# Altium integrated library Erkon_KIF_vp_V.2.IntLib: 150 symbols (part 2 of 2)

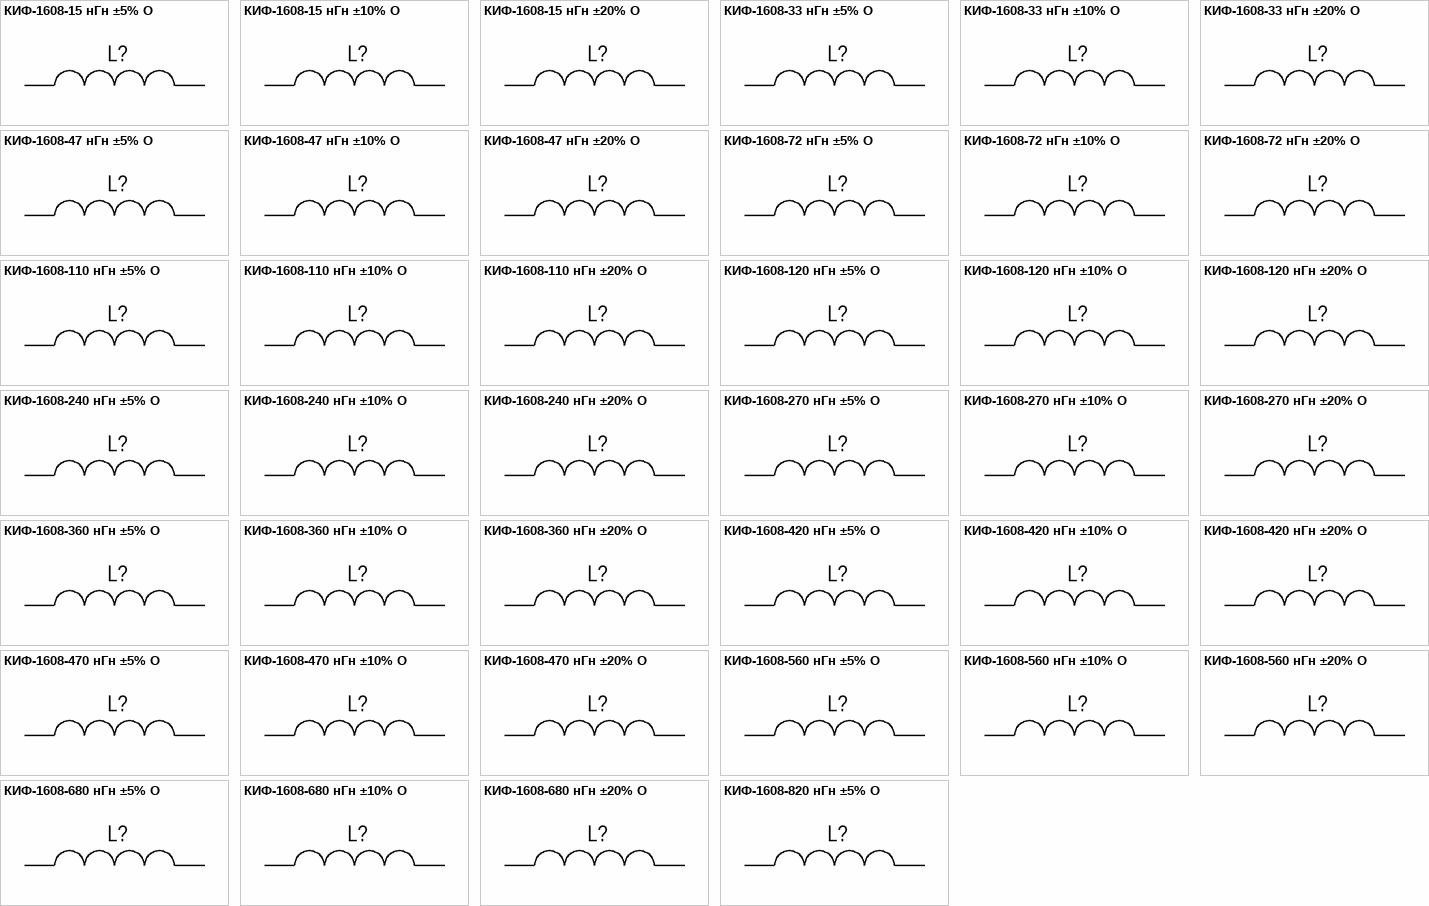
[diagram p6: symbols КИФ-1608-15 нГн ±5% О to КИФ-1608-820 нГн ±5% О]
## КИФ-1608-360 нГн ±10% О
designator L?, comment 360 нГн ±10%  (value not drawn)
Катушка индуктивности с ферритовым сердечником; Номиналиная индуктивность: 360 нГн; Добротность, не менее: 10; Резонансная частота, не менее: 0.7 ГГц; Сопротивление обмотки постоянноми току, не более: 0.33 Ом; Допустимый ток обмотки: 650 мА; Диапазон рабочих температур: от -60 до +125 ℃; Упаковка: Катушка и лента; Типоразмер: 1608 (0603); Технология монтажа: SMT; Изготовитель: АО "НПО "ЭРКОН"
footprint КИФ-1608-О (Катушка индуктивности с ферритовым сердечником типоразмер 1608(0805))
pins: 1, 2

## КИФ-1608-360 нГн ±20% О
designator L?, comment 360 нГн ±20%  (value not drawn)
Катушка индуктивности с ферритовым сердечником; Номиналиная индуктивность: 360 нГн; Добротность, не менее: 10; Резонансная частота, не менее: 0.7 ГГц; Сопротивление обмотки постоянноми току, не более: 0.33 Ом; Допустимый ток обмотки: 650 мА; Диапазон рабочих температур: от -60 до +125 ℃; Упаковка: Катушка и лента; Типоразмер: 1608 (0603); Технология монтажа: SMT; Изготовитель: АО "НПО "ЭРКОН"
footprint КИФ-1608-О (Катушка индуктивности с ферритовым сердечником типоразмер 1608(0805))
pins: 1, 2

## КИФ-1608-420 нГн ±5% О
designator L?, comment 420 нГн ±5%  (value not drawn)
Катушка индуктивности с ферритовым сердечником; Номиналиная индуктивность: 420 нГн; Добротность, не менее: 10; Резонансная частота, не менее: 0.685 ГГц; Сопротивление обмотки постоянноми току, не более: 0.5 Ом; Допустимый ток обмотки: 610 мА; Диапазон рабочих температур: от -60 до +125 ℃; Упаковка: Катушка и лента; Типоразмер: 1608 (0603); Технология монтажа: SMT; Изготовитель: АО "НПО "ЭРКОН"
footprint КИФ-1608-О (Катушка индуктивности с ферритовым сердечником типоразмер 1608(0805))
pins: 1, 2

## КИФ-1608-420 нГн ±10% О
designator L?, comment 420 нГн ±10%  (value not drawn)
Катушка индуктивности с ферритовым сердечником; Номиналиная индуктивность: 420 нГн; Добротность, не менее: 10; Резонансная частота, не менее: 0.685 ГГц; Сопротивление обмотки постоянноми току, не более: 0.5 Ом; Допустимый ток обмотки: 610 мА; Диапазон рабочих температур: от -60 до +125 ℃; Упаковка: Катушка и лента; Типоразмер: 1608 (0603); Технология монтажа: SMT; Изготовитель: АО "НПО "ЭРКОН"
footprint КИФ-1608-О (Катушка индуктивности с ферритовым сердечником типоразмер 1608(0805))
pins: 1, 2

## КИФ-1608-420 нГн ±20% О
designator L?, comment 420 нГн ±20%  (value not drawn)
Катушка индуктивности с ферритовым сердечником; Номиналиная индуктивность: 420 нГн; Добротность, не менее: 10; Резонансная частота, не менее: 0.685 ГГц; Сопротивление обмотки постоянноми току, не более: 0.5 Ом; Допустимый ток обмотки: 610 мА; Диапазон рабочих температур: от -60 до +125 ℃; Упаковка: Катушка и лента; Типоразмер: 1608 (0603); Технология монтажа: SMT; Изготовитель: АО "НПО "ЭРКОН"
footprint КИФ-1608-О (Катушка индуктивности с ферритовым сердечником типоразмер 1608(0805))
pins: 1, 2

## КИФ-1608-470 нГн ±5% О
designator L?, comment 470 нГн ±5%  (value not drawn)
Катушка индуктивности с ферритовым сердечником; Номиналиная индуктивность: 470 нГн; Добротность, не менее: 10; Резонансная частота, не менее: 0.575 ГГц; Сопротивление обмотки постоянноми току, не более: 0.58 Ом; Допустимый ток обмотки: 610 мА; Диапазон рабочих температур: от -60 до +125 ℃; Упаковка: Катушка и лента; Типоразмер: 1608 (0603); Технология монтажа: SMT; Изготовитель: АО "НПО "ЭРКОН"
footprint КИФ-1608-О (Катушка индуктивности с ферритовым сердечником типоразмер 1608(0805))
pins: 1, 2

## КИФ-1608-470 нГн ±10% О
designator L?, comment 470 нГн ±10%  (value not drawn)
Катушка индуктивности с ферритовым сердечником; Номиналиная индуктивность: 470 нГн; Добротность, не менее: 10; Резонансная частота, не менее: 0.575 ГГц; Сопротивление обмотки постоянноми току, не более: 0.58 Ом; Допустимый ток обмотки: 610 мА; Диапазон рабочих температур: от -60 до +125 ℃; Упаковка: Катушка и лента; Типоразмер: 1608 (0603); Технология монтажа: SMT; Изготовитель: АО "НПО "ЭРКОН"
footprint КИФ-1608-О (Катушка индуктивности с ферритовым сердечником типоразмер 1608(0805))
pins: 1, 2

## КИФ-1608-470 нГн ±20% О
designator L?, comment 470 нГн ±20%  (value not drawn)
Катушка индуктивности с ферритовым сердечником; Номиналиная индуктивность: 470 нГн; Добротность, не менее: 10; Резонансная частота, не менее: 0.575 ГГц; Сопротивление обмотки постоянноми току, не более: 0.58 Ом; Допустимый ток обмотки: 610 мА; Диапазон рабочих температур: от -60 до +125 ℃; Упаковка: Катушка и лента; Типоразмер: 1608 (0603); Технология монтажа: SMT; Изготовитель: АО "НПО "ЭРКОН"
footprint КИФ-1608-О (Катушка индуктивности с ферритовым сердечником типоразмер 1608(0805))
pins: 1, 2

## КИФ-1608-560 нГн ±5% О
designator L?, comment 560 нГн ±5%  (value not drawn)
Катушка индуктивности с ферритовым сердечником; Номиналиная индуктивность: 560 нГн; Добротность, не менее: 10; Резонансная частота, не менее: 0.515 ГГц; Сопротивление обмотки постоянноми току, не более: 0.6 Ом; Допустимый ток обмотки: 530 мА; Диапазон рабочих температур: от -60 до +125 ℃; Упаковка: Катушка и лента; Типоразмер: 1608 (0603); Технология монтажа: SMT; Изготовитель: АО "НПО "ЭРКОН"
footprint КИФ-1608-О (Катушка индуктивности с ферритовым сердечником типоразмер 1608(0805))
pins: 1, 2

## КИФ-1608-560 нГн ±10% О
designator L?, comment 560 нГн ±10%  (value not drawn)
Катушка индуктивности с ферритовым сердечником; Номиналиная индуктивность: 560 нГн; Добротность, не менее: 10; Резонансная частота, не менее: 0.515 ГГц; Сопротивление обмотки постоянноми току, не более: 0.6 Ом; Допустимый ток обмотки: 530 мА; Диапазон рабочих температур: от -60 до +125 ℃; Упаковка: Катушка и лента; Типоразмер: 1608 (0603); Технология монтажа: SMT; Изготовитель: АО "НПО "ЭРКОН"
footprint КИФ-1608-О (Катушка индуктивности с ферритовым сердечником типоразмер 1608(0805))
pins: 1, 2

## КИФ-1608-560 нГн ±20% О
designator L?, comment 560 нГн ±20%  (value not drawn)
Катушка индуктивности с ферритовым сердечником; Номиналиная индуктивность: 560 нГн; Добротность, не менее: 10; Резонансная частота, не менее: 0.515 ГГц; Сопротивление обмотки постоянноми току, не более: 0.6 Ом; Допустимый ток обмотки: 530 мА; Диапазон рабочих температур: от -60 до +125 ℃; Упаковка: Катушка и лента; Типоразмер: 1608 (0603); Технология монтажа: SMT; Изготовитель: АО "НПО "ЭРКОН"
footprint КИФ-1608-О (Катушка индуктивности с ферритовым сердечником типоразмер 1608(0805))
pins: 1, 2

## КИФ-1608-680 нГн ±5% О
designator L?, comment 680 нГн ±5%  (value not drawn)
Катушка индуктивности с ферритовым сердечником; Номиналиная индуктивность: 680 нГн; Добротность, не менее: 10; Резонансная частота, не менее: 0.53 ГГц; Сопротивление обмотки постоянноми току, не более: 0.65 Ом; Допустимый ток обмотки: 490 мА; Диапазон рабочих температур: от -60 до +125 ℃; Упаковка: Катушка и лента; Типоразмер: 1608 (0603); Технология монтажа: SMT; Изготовитель: АО "НПО "ЭРКОН"
footprint КИФ-1608-О (Катушка индуктивности с ферритовым сердечником типоразмер 1608(0805))
pins: 1, 2

## КИФ-1608-680 нГн ±10% О
designator L?, comment 680 нГн ±10%  (value not drawn)
Катушка индуктивности с ферритовым сердечником; Номиналиная индуктивность: 680 нГн; Добротность, не менее: 10; Резонансная частота, не менее: 0.53 ГГц; Сопротивление обмотки постоянноми току, не более: 0.65 Ом; Допустимый ток обмотки: 490 мА; Диапазон рабочих температур: от -60 до +125 ℃; Упаковка: Катушка и лента; Типоразмер: 1608 (0603); Технология монтажа: SMT; Изготовитель: АО "НПО "ЭРКОН"
footprint КИФ-1608-О (Катушка индуктивности с ферритовым сердечником типоразмер 1608(0805))
pins: 1, 2

## КИФ-1608-680 нГн ±20% О
designator L?, comment 680 нГн ±20%  (value not drawn)
Катушка индуктивности с ферритовым сердечником; Номиналиная индуктивность: 680 нГн; Добротность, не менее: 10; Резонансная частота, не менее: 0.53 ГГц; Сопротивление обмотки постоянноми току, не более: 0.65 Ом; Допустимый ток обмотки: 490 мА; Диапазон рабочих температур: от -60 до +125 ℃; Упаковка: Катушка и лента; Типоразмер: 1608 (0603); Технология монтажа: SMT; Изготовитель: АО "НПО "ЭРКОН"
footprint КИФ-1608-О (Катушка индуктивности с ферритовым сердечником типоразмер 1608(0805))
pins: 1, 2

## КИФ-1608-820 нГн ±5% О
designator L?, comment 820 нГн ±5%  (value not drawn)
Катушка индуктивности с ферритовым сердечником; Номиналиная индуктивность: 820 нГн; Добротность, не менее: 10; Резонансная частота, не менее: 0.325 ГГц; Сопротивление обмотки постоянноми току, не более: 0.75 Ом; Допустимый ток обмотки: 420 мА; Диапазон рабочих температур: от -60 до +125 ℃; Упаковка: Катушка и лента; Типоразмер: 1608 (0603); Технология монтажа: SMT; Изготовитель: АО "НПО "ЭРКОН"
footprint КИФ-1608-О (Катушка индуктивности с ферритовым сердечником типоразмер 1608(0805))
pins: 1, 2


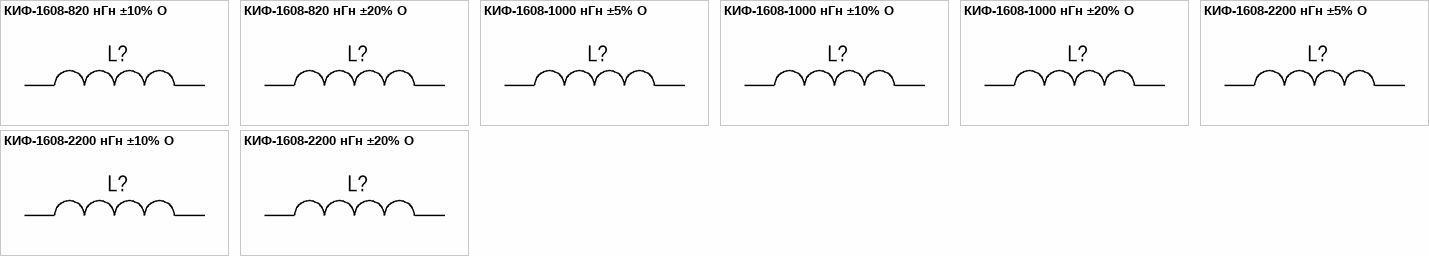
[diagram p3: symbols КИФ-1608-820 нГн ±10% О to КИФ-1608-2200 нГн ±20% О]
## КИФ-1608-820 нГн ±10% О
designator L?, comment 820 нГн ±10%  (value not drawn)
Катушка индуктивности с ферритовым сердечником; Номиналиная индуктивность: 820 нГн; Добротность, не менее: 10; Резонансная частота, не менее: 0.325 ГГц; Сопротивление обмотки постоянноми току, не более: 0.75 Ом; Допустимый ток обмотки: 420 мА; Диапазон рабочих температур: от -60 до +125 ℃; Упаковка: Катушка и лента; Типоразмер: 1608 (0603); Технология монтажа: SMT; Изготовитель: АО "НПО "ЭРКОН"
footprint КИФ-1608-О (Катушка индуктивности с ферритовым сердечником типоразмер 1608(0805))
pins: 1, 2

## КИФ-1608-820 нГн ±20% О
designator L?, comment 820 нГн ±20%  (value not drawn)
Катушка индуктивности с ферритовым сердечником; Номиналиная индуктивность: 820 нГн; Добротность, не менее: 10; Резонансная частота, не менее: 0.325 ГГц; Сопротивление обмотки постоянноми току, не более: 0.75 Ом; Допустимый ток обмотки: 420 мА; Диапазон рабочих температур: от -60 до +125 ℃; Упаковка: Катушка и лента; Типоразмер: 1608 (0603); Технология монтажа: SMT; Изготовитель: АО "НПО "ЭРКОН"
footprint КИФ-1608-О (Катушка индуктивности с ферритовым сердечником типоразмер 1608(0805))
pins: 1, 2

## КИФ-1608-1000 нГн ±5% О
designator L?, comment 1000 нГн ±5%  (value not drawn)
Катушка индуктивности с ферритовым сердечником; Добротность, не менее: 10; Резонансная частота, не менее: 0.4 ГГц; Сопротивление обмотки постоянноми току, не более: 0.8 Ом; Допустимый ток обмотки: 400 мА; Диапазон рабочих температур: от -60 до +125 ℃; Упаковка: Катушка и лента; Типоразмер: 1608 (0603); Технология монтажа: SMT; Изготовитель: АО "НПО "ЭРКОН"
footprint КИФ-1608-О (Катушка индуктивности с ферритовым сердечником типоразмер 1608(0805))
pins: 1, 2

## КИФ-1608-1000 нГн ±10% О
designator L?, comment 1000 нГн ±10%  (value not drawn)
Катушка индуктивности с ферритовым сердечником; Добротность, не менее: 10; Резонансная частота, не менее: 0.4 ГГц; Сопротивление обмотки постоянноми току, не более: 0.8 Ом; Допустимый ток обмотки: 400 мА; Диапазон рабочих температур: от -60 до +125 ℃; Упаковка: Катушка и лента; Типоразмер: 1608 (0603); Технология монтажа: SMT; Изготовитель: АО "НПО "ЭРКОН"
footprint КИФ-1608-О (Катушка индуктивности с ферритовым сердечником типоразмер 1608(0805))
pins: 1, 2

## КИФ-1608-1000 нГн ±20% О
designator L?, comment 1000 нГн ±20%  (value not drawn)
Катушка индуктивности с ферритовым сердечником; Добротность, не менее: 10; Резонансная частота, не менее: 0.4 ГГц; Сопротивление обмотки постоянноми току, не более: 0.8 Ом; Допустимый ток обмотки: 400 мА; Диапазон рабочих температур: от -60 до +125 ℃; Упаковка: Катушка и лента; Типоразмер: 1608 (0603); Технология монтажа: SMT; Изготовитель: АО "НПО "ЭРКОН"
footprint КИФ-1608-О (Катушка индуктивности с ферритовым сердечником типоразмер 1608(0805))
pins: 1, 2

## КИФ-1608-2200 нГн ±5% О
designator L?, comment 2200 нГн ±5%  (value not drawn)
Катушка индуктивности с ферритовым сердечником; Добротность, не менее: 10; Резонансная частота, не менее: 0.085 ГГц; Сопротивление обмотки постоянноми току, не более: 3 Ом; Допустимый ток обмотки: 320 мА; Диапазон рабочих температур: от -60 до +125 ℃; Упаковка: Катушка и лента; Типоразмер: 1608 (0603); Технология монтажа: SMT; Изготовитель: АО "НПО "ЭРКОН"
footprint КИФ-1608-О (Катушка индуктивности с ферритовым сердечником типоразмер 1608(0805))
pins: 1, 2

## КИФ-1608-2200 нГн ±10% О
designator L?, comment 2200 нГн ±10%  (value not drawn)
Катушка индуктивности с ферритовым сердечником; Добротность, не менее: 10; Резонансная частота, не менее: 0.085 ГГц; Сопротивление обмотки постоянноми току, не более: 3 Ом; Допустимый ток обмотки: 320 мА; Диапазон рабочих температур: от -60 до +125 ℃; Упаковка: Катушка и лента; Типоразмер: 1608 (0603); Технология монтажа: SMT; Изготовитель: АО "НПО "ЭРКОН"
footprint КИФ-1608-О (Катушка индуктивности с ферритовым сердечником типоразмер 1608(0805))
pins: 1, 2

## КИФ-1608-2200 нГн ±20% О
designator L?, comment 2200 нГн ±20%  (value not drawn)
Катушка индуктивности с ферритовым сердечником; Добротность, не менее: 10; Резонансная частота, не менее: 0.085 ГГц; Сопротивление обмотки постоянноми току, не более: 3 Ом; Допустимый ток обмотки: 320 мА; Диапазон рабочих температур: от -60 до +125 ℃; Упаковка: Катушка и лента; Типоразмер: 1608 (0603); Технология монтажа: SMT; Изготовитель: АО "НПО "ЭРКОН"
footprint КИФ-1608-О (Катушка индуктивности с ферритовым сердечником типоразмер 1608(0805))
pins: 1, 2



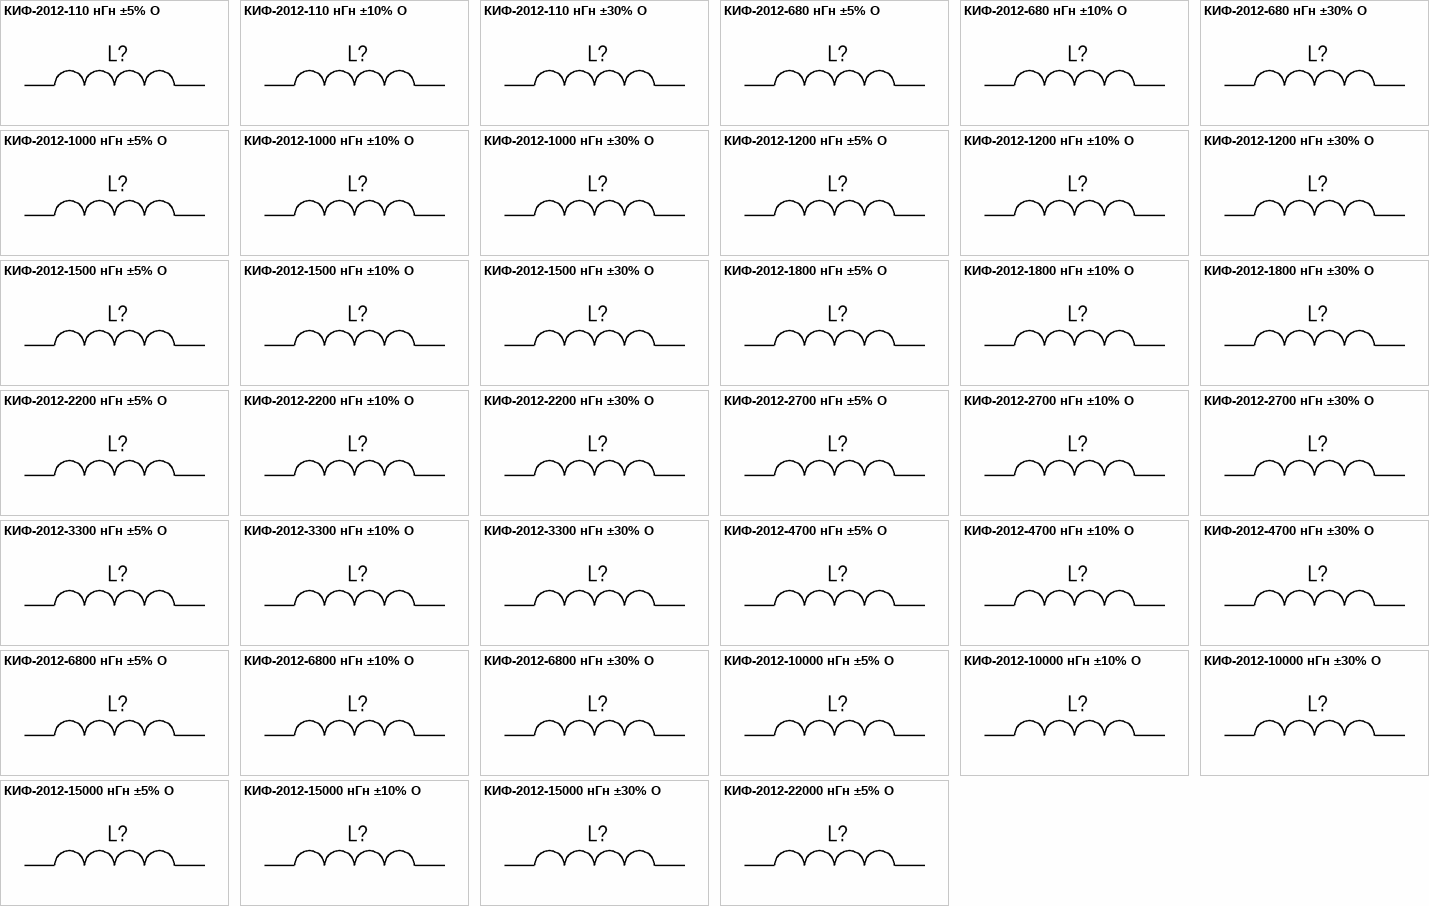
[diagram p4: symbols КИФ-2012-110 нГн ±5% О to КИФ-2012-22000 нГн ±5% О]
## КИФ-2012-110 нГн ±5% О
designator L?, comment 110 нГн ±5%  (value not drawn)
Катушка индуктивности с ферритовым сердечником; Номиналиная индуктивность: 110 нГн; Добротность, не менее: 13; Резонансная частота, не менее: 1,26 ГГц; Сопротивление обмотки постоянноми току, не более: 0.09 Ом; Допустимый ток обмотки: 940 мА; Диапазон рабочих температур: от -60 до +125 ℃; Упаковка: Катушка и лента; Типоразмер: 2012 (0805); Технология монтажа: SMT; Изготовитель: АО "НПО "ЭРКОН"
footprint КИФ-2012-O (Катушка индуктивности с ферритовым сердечником типоразмер 2012(0805))
pins: 1, 2

## КИФ-2012-110 нГн ±10% О
designator L?, comment 110 нГн ±10%  (value not drawn)
Катушка индуктивности с ферритовым сердечником; Номиналиная индуктивность: 110 нГн; Добротность, не менее: 13; Резонансная частота, не менее: 1,26 ГГц; Сопротивление обмотки постоянноми току, не более: 0.09 Ом; Допустимый ток обмотки: 940 мА; Диапазон рабочих температур: от -60 до +125 ℃; Упаковка: Катушка и лента; Типоразмер: 2012 (0805); Технология монтажа: SMT; Изготовитель: АО "НПО "ЭРКОН"
footprint КИФ-2012-O (Катушка индуктивности с ферритовым сердечником типоразмер 2012(0805))
pins: 1, 2

## КИФ-2012-110 нГн ±30% О
designator L?, comment 110 нГн ±30%  (value not drawn)
Катушка индуктивности с ферритовым сердечником; Номиналиная индуктивность: 110 нГн; Добротность, не менее: 13; Резонансная частота, не менее: 1,26 ГГц; Сопротивление обмотки постоянноми току, не более: 0.09 Ом; Допустимый ток обмотки: 940 мА; Диапазон рабочих температур: от -60 до +125 ℃; Упаковка: Катушка и лента; Типоразмер: 2012 (0805); Технология монтажа: SMT; Изготовитель: АО "НПО "ЭРКОН"
footprint КИФ-2012-O (Катушка индуктивности с ферритовым сердечником типоразмер 2012(0805))
pins: 1, 2

## КИФ-2012-680 нГн ±5% О
designator L?, comment 680 нГн ±5%  (value not drawn)
Катушка индуктивности с ферритовым сердечником; Номиналиная индуктивность: 680 нГн; Добротность, не менее: 13; Резонансная частота, не менее: 0,425 ГГц; Сопротивление обмотки постоянноми току, не более: 0.7 Ом; Допустимый ток обмотки: 660 мА; Диапазон рабочих температур: от -60 до +125 ℃; Упаковка: Катушка и лента; Типоразмер: 2012 (0805); Технология монтажа: SMT; Изготовитель: АО "НПО "ЭРКОН"
footprint КИФ-2012-O (Катушка индуктивности с ферритовым сердечником типоразмер 2012(0805))
pins: 1, 2

## КИФ-2012-680 нГн ±10% О
designator L?, comment 680 нГн ±10%  (value not drawn)
Катушка индуктивности с ферритовым сердечником; Номиналиная индуктивность: 680 нГн; Добротность, не менее: 13; Резонансная частота, не менее: 0,425 ГГц; Сопротивление обмотки постоянноми току, не более: 0.7 Ом; Допустимый ток обмотки: 660 мА; Диапазон рабочих температур: от -60 до +125 ℃; Упаковка: Катушка и лента; Типоразмер: 2012 (0805); Технология монтажа: SMT; Изготовитель: АО "НПО "ЭРКОН"
footprint КИФ-2012-O (Катушка индуктивности с ферритовым сердечником типоразмер 2012(0805))
pins: 1, 2

## КИФ-2012-680 нГн ±30% О
designator L?, comment 680 нГн ±30%  (value not drawn)
Катушка индуктивности с ферритовым сердечником; Номиналиная индуктивность: 680 нГн; Добротность, не менее: 13; Резонансная частота, не менее: 0,425 ГГц; Сопротивление обмотки постоянноми току, не более: 0.7 Ом; Допустимый ток обмотки: 660 мА; Диапазон рабочих температур: от -60 до +125 ℃; Упаковка: Катушка и лента; Типоразмер: 2012 (0805); Технология монтажа: SMT; Изготовитель: АО "НПО "ЭРКОН"
footprint КИФ-2012-O (Катушка индуктивности с ферритовым сердечником типоразмер 2012(0805))
pins: 1, 2

## КИФ-2012-1000 нГн ±5% О
designator L?, comment 1000 нГн ±5%  (value not drawn)
Катушка индуктивности с ферритовым сердечником; Добротность, не менее: 13; Резонансная частота, не менее: 0,355 ГГц; Сопротивление обмотки постоянноми току, не более: 0.6 Ом; Допустимый ток обмотки: 650 мА; Диапазон рабочих температур: от -60 до +125 ℃; Упаковка: Катушка и лента; Типоразмер: 2012 (0805); Технология монтажа: SMT; Изготовитель: АО "НПО "ЭРКОН"
footprint КИФ-2012-O (Катушка индуктивности с ферритовым сердечником типоразмер 2012(0805))
pins: 1, 2

## КИФ-2012-1000 нГн ±10% О
designator L?, comment 1000 нГн ±10%  (value not drawn)
Катушка индуктивности с ферритовым сердечником; Добротность, не менее: 13; Резонансная частота, не менее: 0,355 ГГц; Сопротивление обмотки постоянноми току, не более: 0.6 Ом; Допустимый ток обмотки: 650 мА; Диапазон рабочих температур: от -60 до +125 ℃; Упаковка: Катушка и лента; Типоразмер: 2012 (0805); Технология монтажа: SMT; Изготовитель: АО "НПО "ЭРКОН"
footprint КИФ-2012-O (Катушка индуктивности с ферритовым сердечником типоразмер 2012(0805))
pins: 1, 2

## КИФ-2012-1000 нГн ±30% О
designator L?, comment 1000 нГн ±30%  (value not drawn)
Катушка индуктивности с ферритовым сердечником; Добротность, не менее: 13; Резонансная частота, не менее: 0,355 ГГц; Сопротивление обмотки постоянноми току, не более: 0.6 Ом; Допустимый ток обмотки: 650 мА; Диапазон рабочих температур: от -60 до +125 ℃; Упаковка: Катушка и лента; Типоразмер: 2012 (0805); Технология монтажа: SMT; Изготовитель: АО "НПО "ЭРКОН"
footprint КИФ-2012-O (Катушка индуктивности с ферритовым сердечником типоразмер 2012(0805))
pins: 1, 2

## КИФ-2012-1200 нГн ±5% О
designator L?, comment 1200 нГн ±5%  (value not drawn)
Катушка индуктивности с ферритовым сердечником; Добротность, не менее: 13; Резонансная частота, не менее: 0,375 ГГц; Сопротивление обмотки постоянноми току, не более: 0.96 Ом; Допустимый ток обмотки: 440 мА; Диапазон рабочих температур: от -60 до +125 ℃; Упаковка: Катушка и лента; Типоразмер: 2012 (0805); Технология монтажа: SMT; Изготовитель: АО "НПО "ЭРКОН"
footprint КИФ-2012-O (Катушка индуктивности с ферритовым сердечником типоразмер 2012(0805))
pins: 1, 2

## КИФ-2012-1200 нГн ±10% О
designator L?, comment 1200 нГн ±10%  (value not drawn)
Катушка индуктивности с ферритовым сердечником; Добротность, не менее: 13; Резонансная частота, не менее: 0,375 ГГц; Сопротивление обмотки постоянноми току, не более: 0.96 Ом; Допустимый ток обмотки: 440 мА; Диапазон рабочих температур: от -60 до +125 ℃; Упаковка: Катушка и лента; Типоразмер: 2012 (0805); Технология монтажа: SMT; Изготовитель: АО "НПО "ЭРКОН"
footprint КИФ-2012-O (Катушка индуктивности с ферритовым сердечником типоразмер 2012(0805))
pins: 1, 2

## КИФ-2012-1200 нГн ±30% О
designator L?, comment 1200 нГн ±30%  (value not drawn)
Катушка индуктивности с ферритовым сердечником; Добротность, не менее: 13; Резонансная частота, не менее: 0,375 ГГц; Сопротивление обмотки постоянноми току, не более: 0.96 Ом; Допустимый ток обмотки: 440 мА; Диапазон рабочих температур: от -60 до +125 ℃; Упаковка: Катушка и лента; Типоразмер: 2012 (0805); Технология монтажа: SMT; Изготовитель: АО "НПО "ЭРКОН"
footprint КИФ-2012-O (Катушка индуктивности с ферритовым сердечником типоразмер 2012(0805))
pins: 1, 2

## КИФ-2012-1500 нГн ±5% О
designator L?, comment 1500 нГн ±5%  (value not drawn)
Катушка индуктивности с ферритовым сердечником; Добротность, не менее: 13; Резонансная частота, не менее: 0,285 ГГц; Сопротивление обмотки постоянноми току, не более: 1.12 Ом; Допустимый ток обмотки: 390 мА; Диапазон рабочих температур: от -60 до +125 ℃; Упаковка: Катушка и лента; Типоразмер: 2012 (0805); Технология монтажа: SMT; Изготовитель: АО "НПО "ЭРКОН"
footprint КИФ-2012-O (Катушка индуктивности с ферритовым сердечником типоразмер 2012(0805))
pins: 1, 2

## КИФ-2012-1500 нГн ±10% О
designator L?, comment 1500 нГн ±10%  (value not drawn)
Катушка индуктивности с ферритовым сердечником; Добротность, не менее: 13; Резонансная частота, не менее: 0,285 ГГц; Сопротивление обмотки постоянноми току, не более: 1.12 Ом; Допустимый ток обмотки: 390 мА; Диапазон рабочих температур: от -60 до +125 ℃; Упаковка: Катушка и лента; Типоразмер: 2012 (0805); Технология монтажа: SMT; Изготовитель: АО "НПО "ЭРКОН"
footprint КИФ-2012-O (Катушка индуктивности с ферритовым сердечником типоразмер 2012(0805))
pins: 1, 2

## КИФ-2012-1500 нГн ±30% О
designator L?, comment 1500 нГн ±30%  (value not drawn)
Катушка индуктивности с ферритовым сердечником; Добротность, не менее: 13; Резонансная частота, не менее: 0,285 ГГц; Сопротивление обмотки постоянноми току, не более: 1.12 Ом; Допустимый ток обмотки: 390 мА; Диапазон рабочих температур: от -60 до +125 ℃; Упаковка: Катушка и лента; Типоразмер: 2012 (0805); Технология монтажа: SMT; Изготовитель: АО "НПО "ЭРКОН"
footprint КИФ-2012-O (Катушка индуктивности с ферритовым сердечником типоразмер 2012(0805))
pins: 1, 2

## КИФ-2012-1800 нГн ±5% О
designator L?, comment 1800 нГн ±5%  (value not drawn)
Катушка индуктивности с ферритовым сердечником; Добротность, не менее: 13; Резонансная частота, не менее: 0,3 ГГц; Сопротивление обмотки постоянноми току, не более: 1.2 Ом; Допустимый ток обмотки: 370 мА; Диапазон рабочих температур: от -60 до +125 ℃; Упаковка: Катушка и лента; Типоразмер: 2012 (0805); Технология монтажа: SMT; Изготовитель: АО "НПО "ЭРКОН"
footprint КИФ-2012-O (Катушка индуктивности с ферритовым сердечником типоразмер 2012(0805))
pins: 1, 2

## КИФ-2012-1800 нГн ±10% О
designator L?, comment 1800 нГн ±10%  (value not drawn)
Катушка индуктивности с ферритовым сердечником; Добротность, не менее: 13; Резонансная частота, не менее: 0.3 ГГц; Сопротивление обмотки постоянноми току, не более: 1.2 Ом; Допустимый ток обмотки: 370 мА; Диапазон рабочих температур: от -60 до +125 ℃; Упаковка: Катушка и лента; Типоразмер: 2012 (0805); Технология монтажа: SMT; Изготовитель: АО "НПО "ЭРКОН"
footprint КИФ-2012-O (Катушка индуктивности с ферритовым сердечником типоразмер 2012(0805))
pins: 1, 2

## КИФ-2012-1800 нГн ±30% О
designator L?, comment 1800 нГн ±30%  (value not drawn)
Катушка индуктивности с ферритовым сердечником; Добротность, не менее: 13; Резонансная частота, не менее: 0.3 ГГц; Сопротивление обмотки постоянноми току, не более: 1.2 Ом; Допустимый ток обмотки: 370 мА; Диапазон рабочих температур: от -60 до +125 ℃; Упаковка: Катушка и лента; Типоразмер: 2012 (0805); Технология монтажа: SMT; Изготовитель: АО "НПО "ЭРКОН"
footprint КИФ-2012-O (Катушка индуктивности с ферритовым сердечником типоразмер 2012(0805))
pins: 1, 2

## КИФ-2012-2200 нГн ±5% О
designator L?, comment 2200 нГн ±5%  (value not drawn)
Катушка индуктивности с ферритовым сердечником; Добротность, не менее: 13; Резонансная частота, не менее: 0.105 ГГц; Сопротивление обмотки постоянноми току, не более: 1.47 Ом; Допустимый ток обмотки: 350 мА; Диапазон рабочих температур: от -60 до +125 ℃; Упаковка: Катушка и лента; Типоразмер: 2012 (0805); Технология монтажа: SMT; Изготовитель: АО "НПО "ЭРКОН"
footprint КИФ-2012-O (Катушка индуктивности с ферритовым сердечником типоразмер 2012(0805))
pins: 1, 2

## КИФ-2012-2200 нГн ±10% О
designator L?, comment 2200 нГн ±10%  (value not drawn)
Катушка индуктивности с ферритовым сердечником; Добротность, не менее: 13; Резонансная частота, не менее: 0.105 ГГц; Сопротивление обмотки постоянноми току, не более: 1.47 Ом; Допустимый ток обмотки: 350 мА; Диапазон рабочих температур: от -60 до +125 ℃; Упаковка: Катушка и лента; Типоразмер: 2012 (0805); Технология монтажа: SMT; Изготовитель: АО "НПО "ЭРКОН"
footprint КИФ-2012-O (Катушка индуктивности с ферритовым сердечником типоразмер 2012(0805))
pins: 1, 2

## КИФ-2012-2200 нГн ±30% О
designator L?, comment 2200 нГн ±30%  (value not drawn)
Катушка индуктивности с ферритовым сердечником; Добротность, не менее: 13; Резонансная частота, не менее: 0.105 ГГц; Сопротивление обмотки постоянноми току, не более: 1.47 Ом; Допустимый ток обмотки: 350 мА; Диапазон рабочих температур: от -60 до +125 ℃; Упаковка: Катушка и лента; Типоразмер: 2012 (0805); Технология монтажа: SMT; Изготовитель: АО "НПО "ЭРКОН"
footprint КИФ-2012-O (Катушка индуктивности с ферритовым сердечником типоразмер 2012(0805))
pins: 1, 2

## КИФ-2012-2700 нГн ±5% О
designator L?, comment 2700 нГн ±5%  (value not drawn)
Катушка индуктивности с ферритовым сердечником; Добротность, не менее: 13; Резонансная частота, не менее: 0.10 ГГц; Сопротивление обмотки постоянноми току, не более: 1.7 Ом; Допустимый ток обмотки: 320 мА; Диапазон рабочих температур: от -60 до +125 ℃; Упаковка: Катушка и лента; Типоразмер: 2012 (0805); Технология монтажа: SMT; Изготовитель: АО "НПО "ЭРКОН"
footprint КИФ-2012-O (Катушка индуктивности с ферритовым сердечником типоразмер 2012(0805))
pins: 1, 2

## КИФ-2012-2700 нГн ±10% О
designator L?, comment 2700 нГн ±10%  (value not drawn)
Катушка индуктивности с ферритовым сердечником; Добротность, не менее: 13; Резонансная частота, не менее: 0.10 ГГц; Сопротивление обмотки постоянноми току, не более: 1.7 Ом; Допустимый ток обмотки: 320 мА; Диапазон рабочих температур: от -60 до +125 ℃; Упаковка: Катушка и лента; Типоразмер: 2012 (0805); Технология монтажа: SMT; Изготовитель: АО "НПО "ЭРКОН"
footprint КИФ-2012-O (Катушка индуктивности с ферритовым сердечником типоразмер 2012(0805))
pins: 1, 2

## КИФ-2012-2700 нГн ±30% О
designator L?, comment 2700 нГн ±30%  (value not drawn)
Катушка индуктивности с ферритовым сердечником; Добротность, не менее: 13; Резонансная частота, не менее: 0.10 ГГц; Сопротивление обмотки постоянноми току, не более: 1.7 Ом; Допустимый ток обмотки: 320 мА; Диапазон рабочих температур: от -60 до +125 ℃; Упаковка: Катушка и лента; Типоразмер: 2012 (0805); Технология монтажа: SMT; Изготовитель: АО "НПО "ЭРКОН"
footprint КИФ-2012-O (Катушка индуктивности с ферритовым сердечником типоразмер 2012(0805))
pins: 1, 2

## КИФ-2012-3300 нГн ±5% О
designator L?, comment 3300 нГн ±5%  (value not drawn)
Катушка индуктивности с ферритовым сердечником; Добротность, не менее: 13; Резонансная частота, не менее: 0.085 ГГц; Сопротивление обмотки постоянноми току, не более: 1.8 Ом; Допустимый ток обмотки: 330 мА; Диапазон рабочих температур: от -60 до +125 ℃; Упаковка: Катушка и лента; Типоразмер: 2012 (0805); Технология монтажа: SMT; Изготовитель: АО "НПО "ЭРКОН"
footprint КИФ-2012-O (Катушка индуктивности с ферритовым сердечником типоразмер 2012(0805))
pins: 1, 2

## КИФ-2012-3300 нГн ±10% О
designator L?, comment 3300 нГн ±10%  (value not drawn)
Катушка индуктивности с ферритовым сердечником; Добротность, не менее: 13; Резонансная частота, не менее: 0.085 ГГц; Сопротивление обмотки постоянноми току, не более: 1.8 Ом; Допустимый ток обмотки: 330 мА; Диапазон рабочих температур: от -60 до +125 ℃; Упаковка: Катушка и лента; Типоразмер: 2012 (0805); Технология монтажа: SMT; Изготовитель: АО "НПО "ЭРКОН"
footprint КИФ-2012-O (Катушка индуктивности с ферритовым сердечником типоразмер 2012(0805))
pins: 1, 2

## КИФ-2012-3300 нГн ±30% О
designator L?, comment 3300 нГн ±30%  (value not drawn)
Катушка индуктивности с ферритовым сердечником; Добротность, не менее: 13; Резонансная частота, не менее: 0.085 ГГц; Сопротивление обмотки постоянноми току, не более: 1.8 Ом; Допустимый ток обмотки: 330 мА; Диапазон рабочих температур: от -60 до +125 ℃; Упаковка: Катушка и лента; Типоразмер: 2012 (0805); Технология монтажа: SMT; Изготовитель: АО "НПО "ЭРКОН"
footprint КИФ-2012-O (Катушка индуктивности с ферритовым сердечником типоразмер 2012(0805))
pins: 1, 2

## КИФ-2012-4700 нГн ±5% О
designator L?, comment 4700 нГн ±5%  (value not drawn)
Катушка индуктивности с ферритовым сердечником; Добротность, не менее: 13; Резонансная частота, не менее: 0.055 ГГц; Сопротивление обмотки постоянноми току, не более: 2.2 Ом; Допустимый ток обмотки: 280 мА; Диапазон рабочих температур: от -60 до +125 ℃; Упаковка: Катушка и лента; Типоразмер: 2012 (0805); Технология монтажа: SMT; Изготовитель: АО "НПО "ЭРКОН"
footprint КИФ-2012-O (Катушка индуктивности с ферритовым сердечником типоразмер 2012(0805))
pins: 1, 2

## КИФ-2012-4700 нГн ±10% О
designator L?, comment 4700 нГн ±10%  (value not drawn)
Катушка индуктивности с ферритовым сердечником; Добротность, не менее: 13; Резонансная частота, не менее: 0.055 ГГц; Сопротивление обмотки постоянноми току, не более: 2.2 Ом; Допустимый ток обмотки: 280 мА; Диапазон рабочих температур: от -60 до +125 ℃; Упаковка: Катушка и лента; Типоразмер: 2012 (0805); Технология монтажа: SMT; Изготовитель: АО "НПО "ЭРКОН"
footprint КИФ-2012-O (Катушка индуктивности с ферритовым сердечником типоразмер 2012(0805))
pins: 1, 2

## КИФ-2012-4700 нГн ±30% О
designator L?, comment 4700 нГн ±30%  (value not drawn)
Катушка индуктивности с ферритовым сердечником; Добротность, не менее: 13; Резонансная частота, не менее: 0.055 ГГц; Сопротивление обмотки постоянноми току, не более: 2.2 Ом; Допустимый ток обмотки: 280 мА; Диапазон рабочих температур: от -60 до +125 ℃; Упаковка: Катушка и лента; Типоразмер: 2012 (0805); Технология монтажа: SMT; Изготовитель: АО "НПО "ЭРКОН"
footprint КИФ-2012-O (Катушка индуктивности с ферритовым сердечником типоразмер 2012(0805))
pins: 1, 2

## КИФ-2012-6800 нГн ±5% О
designator L?, comment 6800 нГн ±5%  (value not drawn)
Катушка индуктивности с ферритовым сердечником; Добротность, не менее: 13; Резонансная частота, не менее: 0.035 ГГц; Сопротивление обмотки постоянноми току, не более: 2.8 Ом; Допустимый ток обмотки: 240 мА; Диапазон рабочих температур: от -60 до +125 ℃; Упаковка: Катушка и лента; Типоразмер: 2012 (0805); Технология монтажа: SMT; Изготовитель: АО "НПО "ЭРКОН"
footprint КИФ-2012-O (Катушка индуктивности с ферритовым сердечником типоразмер 2012(0805))
pins: 1, 2

## КИФ-2012-6800 нГн ±10% О
designator L?, comment 6800 нГн ±10%  (value not drawn)
Катушка индуктивности с ферритовым сердечником; Добротность, не менее: 13; Резонансная частота, не менее: 0.035 ГГц; Сопротивление обмотки постоянноми току, не более: 2.8 Ом; Допустимый ток обмотки: 240 мА; Диапазон рабочих температур: от -60 до +125 ℃; Упаковка: Катушка и лента; Типоразмер: 2012 (0805); Технология монтажа: SMT; Изготовитель: АО "НПО "ЭРКОН"
footprint КИФ-2012-O (Катушка индуктивности с ферритовым сердечником типоразмер 2012(0805))
pins: 1, 2

## КИФ-2012-6800 нГн ±30% О
designator L?, comment 6800 нГн ±30%  (value not drawn)
Катушка индуктивности с ферритовым сердечником; Добротность, не менее: 13; Резонансная частота, не менее: 0.035 ГГц; Сопротивление обмотки постоянноми току, не более: 2.8 Ом; Допустимый ток обмотки: 240 мА; Диапазон рабочих температур: от -60 до +125 ℃; Упаковка: Катушка и лента; Типоразмер: 2012 (0805); Технология монтажа: SMT; Изготовитель: АО "НПО "ЭРКОН"
footprint КИФ-2012-O (Катушка индуктивности с ферритовым сердечником типоразмер 2012(0805))
pins: 1, 2

## КИФ-2012-10000 нГн ±5% О
designator L?, comment 10000 нГн ±5%  (value not drawn)
Катушка индуктивности с ферритовым сердечником; Добротность, не менее: 13; Резонансная частота, не менее: 0.019 ГГц; Сопротивление обмотки постоянноми току, не более: 3.3 Ом; Допустимый ток обмотки: 230 мА; Диапазон рабочих температур: от -60 до +125 ℃; Упаковка: Катушка и лента; Типоразмер: 2012 (0805); Технология монтажа: SMT; Изготовитель: АО "НПО "ЭРКОН"
footprint КИФ-2012-O (Катушка индуктивности с ферритовым сердечником типоразмер 2012(0805))
pins: 1, 2

## КИФ-2012-10000 нГн ±10% О
designator L?, comment 10000 нГн ±10%  (value not drawn)
Катушка индуктивности с ферритовым сердечником; Добротность, не менее: 13; Резонансная частота, не менее: 0.019 ГГц; Сопротивление обмотки постоянноми току, не более: 3.3 Ом; Допустимый ток обмотки: 230 мА; Диапазон рабочих температур: от -60 до +125 ℃; Упаковка: Катушка и лента; Типоразмер: 2012 (0805); Технология монтажа: SMT; Изготовитель: АО "НПО "ЭРКОН"
footprint КИФ-2012-O (Катушка индуктивности с ферритовым сердечником типоразмер 2012(0805))
pins: 1, 2

## КИФ-2012-10000 нГн ±30% О
designator L?, comment 10000 нГн ±30%  (value not drawn)
Катушка индуктивности с ферритовым сердечником; Добротность, не менее: 13; Резонансная частота, не менее: 0.019 ГГц; Сопротивление обмотки постоянноми току, не более: 3.3 Ом; Допустимый ток обмотки: 230 мА; Диапазон рабочих температур: от -60 до +125 ℃; Упаковка: Катушка и лента; Типоразмер: 2012 (0805); Технология монтажа: SMT; Изготовитель: АО "НПО "ЭРКОН"
footprint КИФ-2012-O (Катушка индуктивности с ферритовым сердечником типоразмер 2012(0805))
pins: 1, 2

## КИФ-2012-15000 нГн ±5% О
designator L?, comment 15000 нГн ±5%  (value not drawn)
Катушка индуктивности с ферритовым сердечником; Добротность, не менее: 13; Резонансная частота, не менее: 0.015 ГГц; Сопротивление обмотки постоянноми току, не более: 6.3 Ом; Допустимый ток обмотки: 150 мА; Диапазон рабочих температур: от -60 до +125 ℃; Упаковка: Катушка и лента; Типоразмер: 2012 (0805); Технология монтажа: SMT; Изготовитель: АО "НПО "ЭРКОН"
footprint КИФ-2012-O (Катушка индуктивности с ферритовым сердечником типоразмер 2012(0805))
pins: 1, 2

## КИФ-2012-15000 нГн ±10% О
designator L?, comment 15000 нГн ±10%  (value not drawn)
Катушка индуктивности с ферритовым сердечником; Добротность, не менее: 13; Резонансная частота, не менее: 0.015 ГГц; Сопротивление обмотки постоянноми току, не более: 6.3 Ом; Допустимый ток обмотки: 150 мА; Диапазон рабочих температур: от -60 до +125 ℃; Упаковка: Катушка и лента; Типоразмер: 2012 (0805); Технология монтажа: SMT; Изготовитель: АО "НПО "ЭРКОН"
footprint КИФ-2012-O (Катушка индуктивности с ферритовым сердечником типоразмер 2012(0805))
pins: 1, 2

## КИФ-2012-15000 нГн ±30% О
designator L?, comment 15000 нГн ±30%  (value not drawn)
Катушка индуктивности с ферритовым сердечником; Допускаемое отклонение индуктивности: ±10%; Добротность, не менее: 13; Резонансная частота, не менее: 0.015 ГГц; Сопротивление обмотки постоянноми току, не более: 6.3 Ом; Допустимый ток обмотки: 150 мА; Диапазон рабочих температур: от -60 до +125 ℃; Упаковка: Катушка и лента; Типоразмер: 2012 (0805); Технология монтажа: SMT; Изготовитель: АО "НПО "ЭРКОН"
footprint КИФ-2012-O (Катушка индуктивности с ферритовым сердечником типоразмер 2012(0805))
pins: 1, 2

## КИФ-2012-22000 нГн ±5% О
designator L?, comment 22000 нГн ±5%  (value not drawn)
Катушка индуктивности с ферритовым сердечником; Добротность, не менее: 13; Резонансная частота, не менее: 0.01 ГГц; Сопротивление обмотки постоянноми току, не более: 10 Ом; Допустимый ток обмотки: 120 мА; Диапазон рабочих температур: от -60 до +125 ℃; Упаковка: Катушка и лента; Типоразмер: 2012 (0805); Технология монтажа: SMT; Изготовитель: АО "НПО "ЭРКОН"
footprint КИФ-2012-O (Катушка индуктивности с ферритовым сердечником типоразмер 2012(0805))
pins: 1, 2


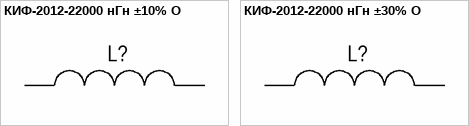
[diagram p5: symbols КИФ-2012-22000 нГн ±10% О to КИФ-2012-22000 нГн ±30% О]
## КИФ-2012-22000 нГн ±10% О
designator L?, comment 22000 нГн ±10%  (value not drawn)
Катушка индуктивности с ферритовым сердечником; Добротность, не менее: 13; Резонансная частота, не менее: 0.01 ГГц; Сопротивление обмотки постоянноми току, не более: 10 Ом; Допустимый ток обмотки: 120 мА; Диапазон рабочих температур: от -60 до +125 ℃; Упаковка: Катушка и лента; Типоразмер: 2012 (0805); Технология монтажа: SMT; Изготовитель: АО "НПО "ЭРКОН"
footprint КИФ-2012-O (Катушка индуктивности с ферритовым сердечником типоразмер 2012(0805))
pins: 1, 2

## КИФ-2012-22000 нГн ±30% О
designator L?, comment 22000 нГн ±30%  (value not drawn)
Катушка индуктивности с ферритовым сердечником; Добротность, не менее: 13; Резонансная частота, не менее: 0.01 ГГц; Сопротивление обмотки постоянноми току, не более: 10 Ом; Допустимый ток обмотки: 120 мА; Диапазон рабочих температур: от -60 до +125 ℃; Упаковка: Катушка и лента; Типоразмер: 2012 (0805); Технология монтажа: SMT; Изготовитель: АО "НПО "ЭРКОН"
footprint КИФ-2012-O (Катушка индуктивности с ферритовым сердечником типоразмер 2012(0805))
pins: 1, 2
